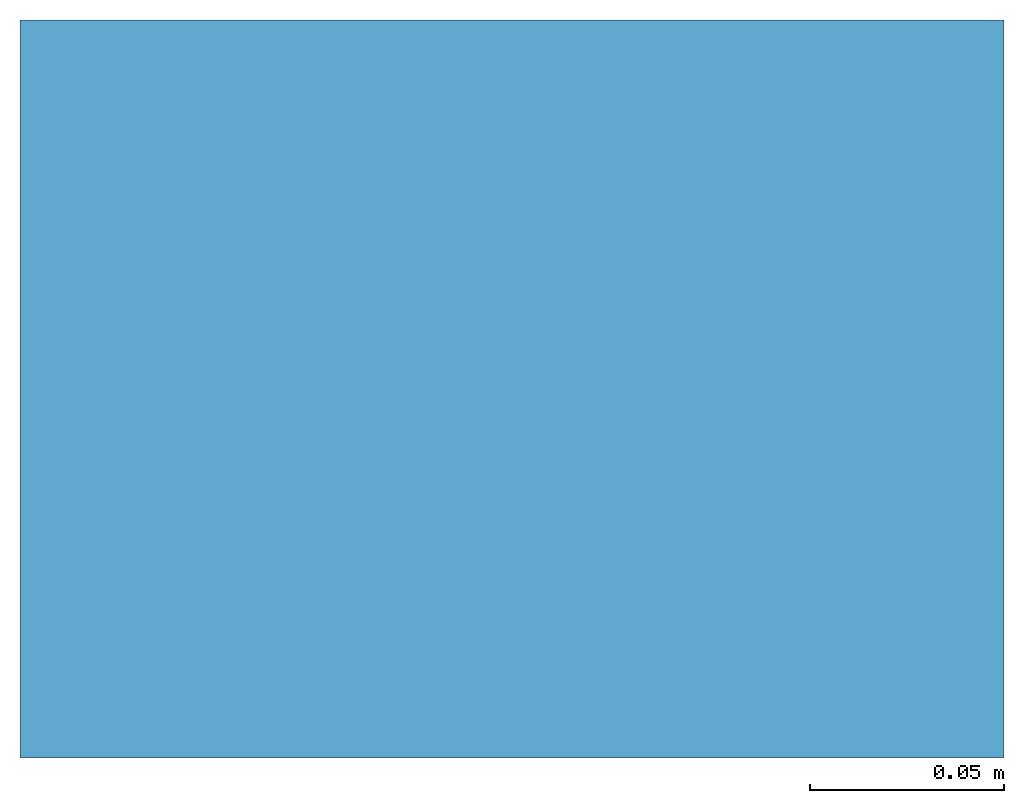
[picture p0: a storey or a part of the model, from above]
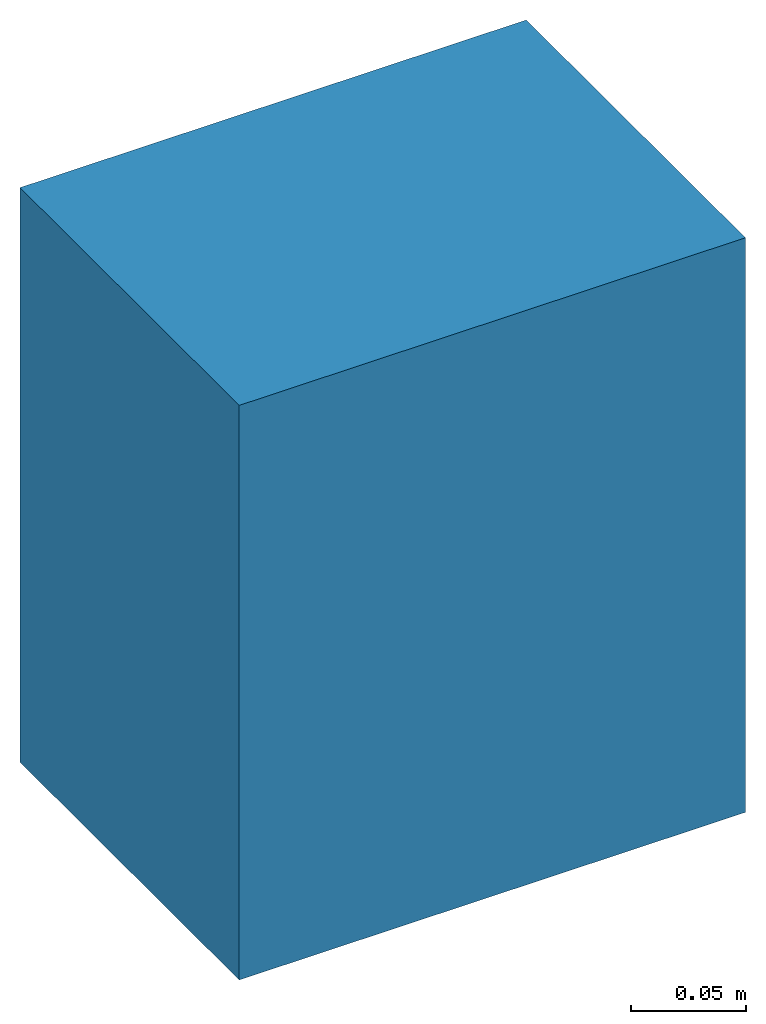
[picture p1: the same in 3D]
Properties of the parts of a building model (IFC2X3)

# File
Description: ViewDefinition [CoordinationView_V2.0]
File name: Project Number
Time: 2021-12-21T08:16:22
Written by: The EXPRESS Data Manager Version 5.02.0100.07 : 28 Aug 2013
Made in: 20190731_1515(x64) - Exporter 20.1.1.1 - Alternate UI 20.1.1.1
Comment: STEP Physical File produced by: The EXPRESS Data Manager Version 5.02.0100.07 : 28 Aug 2013 * Module: EDMstepFileFactory/EDMstandAlone * Creation date: Tue Dec 21 08:16:22 2021 * Host: LT-GBA1 * Database: C:\Users\gba\AppData\Local\Temp\e1309e90-b227-4c61-993d-2ed405d2fde1\f490b3e3-3c7a-4a65-a07c-6c99a4fbc629\ifc * Database version: 5507 * Database creation date: Tue Dec 21 08:16:18 2021 * Schema: IFC2X3 * Model: DataRepository.ifc * Model creation date: Tue Dec 21 08:16:18 2021 * Header model: DataRepository.ifc_HeaderModel * Header model creation date: Tue Dec 21 08:16:18 2021 * EDMuser: sdai-user * EDMgroup: sdai-group * License ID and type: 5605 : Permanent license. Expiry date: * EDMstepFileFactory options: 020000

# IfcProject, Project Number
LongName: Project Name; Phase: Project Status

# IfcSite, Default
RefLatitude: 42, 21, 31, 181945; RefLongitude: -71, -3, -24, -263305; RefElevation: 0 ft

# IfcBuilding
Pset_BuildingCommon - NumberOfStoreys: 1
Pset_ProductRequirements - Category: Project Information

# IfcBuildingStorey: Level:1/4" Head, Level 1
LongName: Level 1; Elevation: 0 ft
Pset_AirSideSystemInformation - Name: Level 1
Pset_ProductRequirements - Name: Level 1; Category: Levels

# IfcSlab: Floor:Generic - 12", Floor:Generic - 12":339165
In: Level 1
Type - PredefinedType: FLOOR; Material: Default Floor 1 ft
Type - Pset_ElementShading - Roughness: 1 ft
Type - Pset_ProductRequirements - Category: Floors
Type - Pset_QuantityTakeOff - Reference: Generic - 12"
Type - Pset_ReinforcementBarPitchOfSlab - Reference: Generic - 12"
Type - Pset_SlabCommon - Reference: Generic - 12"; IsExternal: no
Classification: B1010 Floor Construction (Uniformat)
Pset_QuantityTakeOff - sets with these values: 2
Pset_SlabCommon - LoadBearing: no; PitchAngle: 0 deg
